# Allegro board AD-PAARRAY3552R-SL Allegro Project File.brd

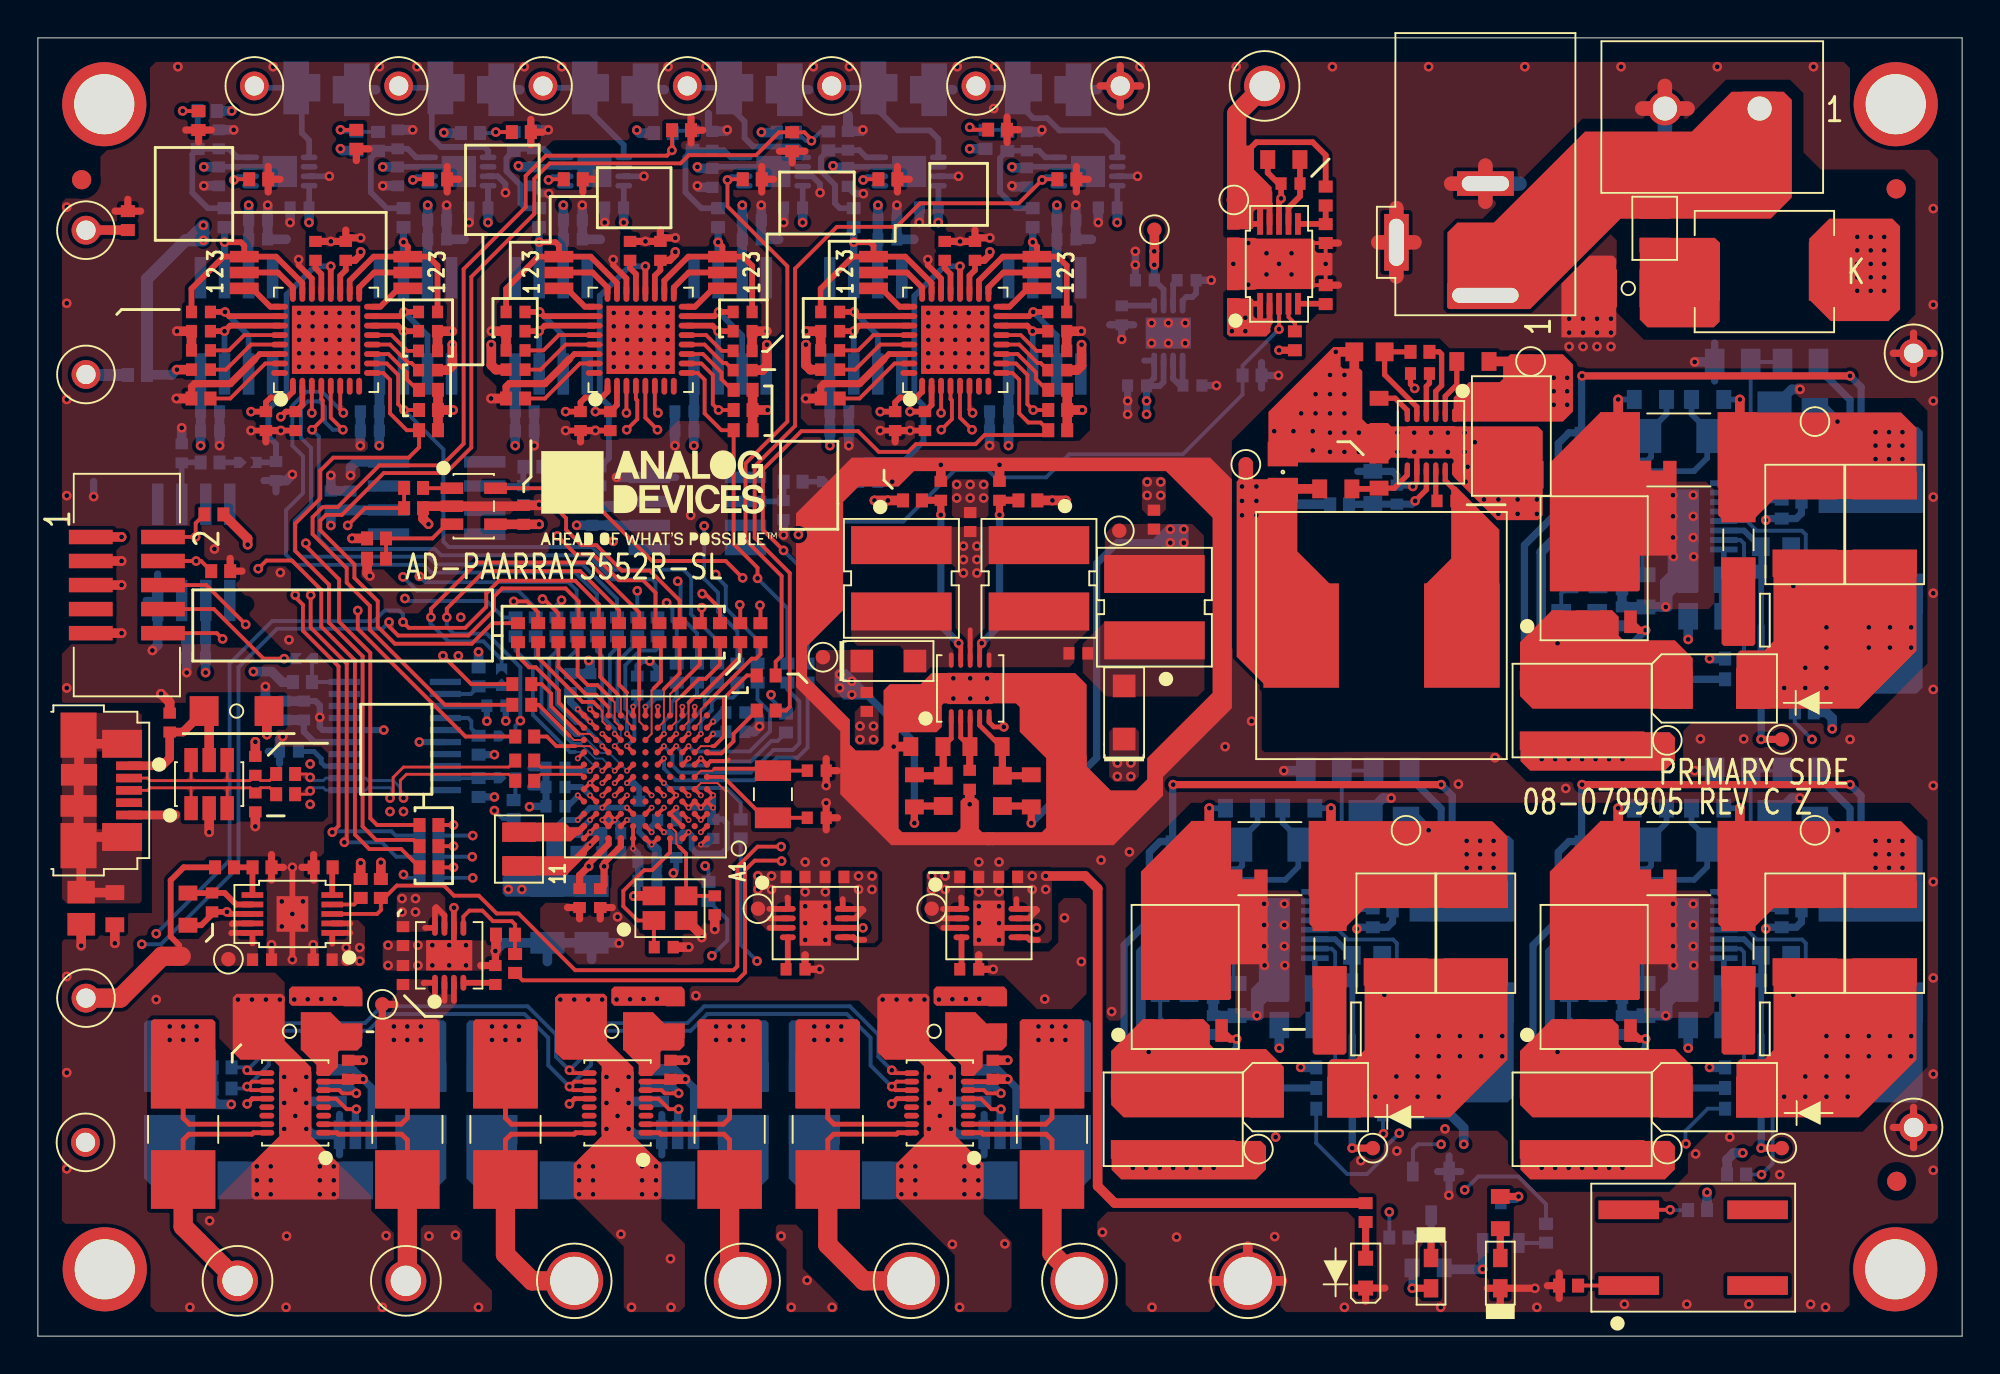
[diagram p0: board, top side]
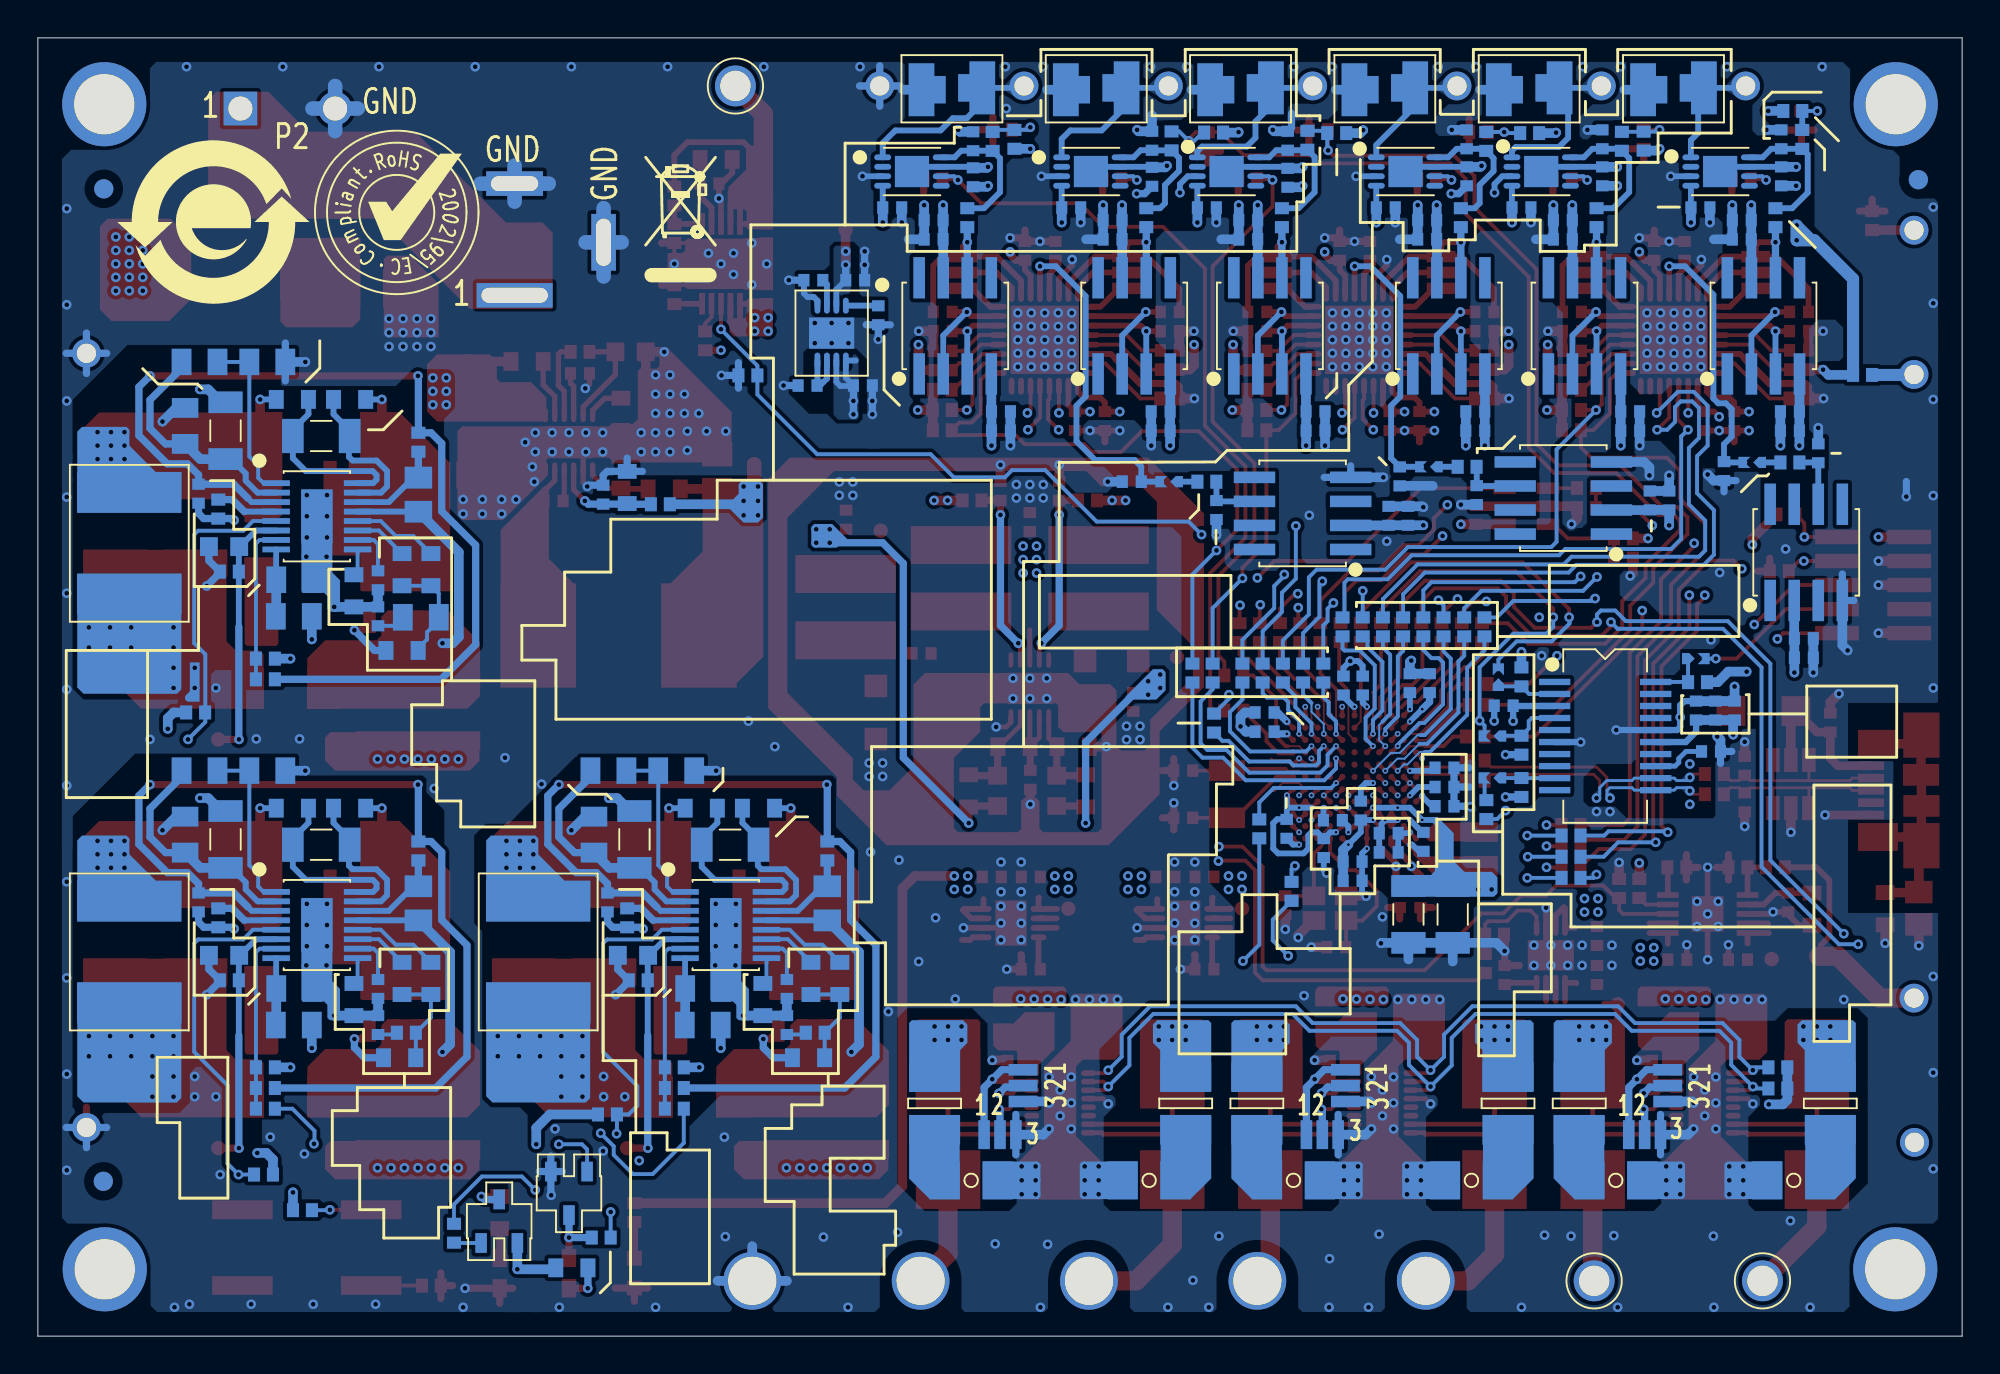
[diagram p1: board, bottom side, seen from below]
Outline 101.6 x 68.58 mm; copper layers: TOP, L2_GND, L3_SIG, L4_PWR, L5_GND, BOTTOM. Coordinates in mm from the lower left corner of the outline.
Outline path: 0,68.58 0,0 101.6,0 101.6,68.58 0,68.58

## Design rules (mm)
constraint set DEFAULT: min track width 0.203
net group DM_32666: nets DM_32666 UNNAMED_20_ADMAX3207E_I10_I
net group DP_32666: nets DP_32666 UNNAMED_20_ADMAX3207E_I10_I_1
net group USB_R: nets UNNAMED_19_ADMAX32666_I33_DM UNNAMED_19_ADMAX32666_I33_DP

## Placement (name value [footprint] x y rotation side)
A1  AD8065ARZ  [SO8]  43.71 53.37 180 bottom
A2  AD8065ARZ  [SO8]  53.16 53.37 180 bottom
A3  AD8065ARZ  [SO8]  27.1 53.37 180 bottom
A4  AD8065ARZ  [SO8]  36.55 53.37 180 bottom
A5  AD8065ARZ  [SO8]  10.49 53.37 180 bottom
A6  AD8065ARZ  [SO8]  19.94 53.37 180 bottom
C1  150NF  [C1206H71]  83.97 55.35 0 top
C2  10NF  [C1206H64]  89.79 20.47 90 top
C3  0.1uF  [C1206]  91.69 26.24 90 bottom
C4  22UF  [C2220H264]  96.77 20.29 90 bottom
C5  1UF  [C1812H100]  97.51 21.29 90 top
C6  1UF  [C1812H100]  93.29 21.29 90 top
C7  390PF  [C0603]  91.77 20.12 0 bottom
C8  0.1uF  [C1206]  86.64 25.96 0 bottom
C9  0.1UF  [C0805]  81.51 22.86 270 bottom
C10  1UF  [C0402]  83.64 16.43 90 bottom
C11  1NF  [C0402]  83.64 18.34 270 bottom
C12  1UF  [C0402]  93.12 22.91 270 bottom
C13  10NF  [C1206H64]  89.79 42.06 90 top
C14  22UF  [C2220H264]  96.77 41.88 90 bottom
C15  1UF  [C1812H100]  97.51 42.88 90 top
C16  1UF  [C1812H100]  93.29 42.88 90 top
C17  0.1uF  [C1206]  91.69 47.83 90 bottom
C18  390PF  [C0603]  91.77 41.71 0 bottom
C19  0.1uF  [C1206]  86.64 47.55 0 bottom
C20  0.1UF  [C0805]  81.51 44.45 270 bottom
C21  1UF  [C0402]  83.64 38.02 90 bottom
C22  1NF  [C0402]  83.64 39.93 270 bottom
C23  1UF  [C0402]  93.12 44.5 270 bottom
C24  4.7uF  [C0402]  63.12 55.04 90 top
C25  4.7uF  [C0402]  15.04 19.89 180 top
C26  4.7uF  [C0402]  19.28 21.13 270 top
C27  1UF  [C1812H100]  77.8 47.55 270 top
C28  0.056uF  [C0402]  72.97 50.85 180 top
C29  2.2UF  [C0603]  70.31 51.99 180 top
C30  1NF  [C0402]  24.16 19.08 90 top
C31  4.7uF  [C0402]  19.28 19.08 90 top
C32  4.7uF  [C0402]  66.14 60.88 180 top
C33  4.7uF  [C0402]  9.19 22.91 270 top
C34  100NF  [C0402]  74.37 44.12 180 top
C35  4.7uF  [C0402]  63.12 58.24 270 top
C36  4.7uF  [C0402]  11.84 19.89 0 top
C37  100NF  [C0402]  71.75 44.45 270 bottom
C38  6.8uF  [C0805H60]  65.74 45.64 90 top
C39  4.7uF  [C0402]  51.23 24.26 180 top
C40  4.7uF  [C0402]  42.06 24.26 180 top
C41  10UF  [C0402]  58.04 50.22 180 bottom
C42  1UF  [C0402]  60.66 55.78 0 bottom
C43  0.33uF  [C0402]  47.68 44.65 270 top
C44  4.7uF  [C0402]  49.23 43 90 top
C45  10UF  [C0402]  57.23 53.92 270 bottom
C46  1NF  [C0402]  49.17 19.38 0 top
C47  1NF  [C0402]  40 19.38 0 top
C48  0.33uF  [C0402]  50.77 44.65 270 top
C49  4.7uF  [C0402]  49.17 24.26 0 top
C50  4.7uF  [C0402]  40 24.26 0 top
C51  1UF  [C0402]  60.96 50.22 0 bottom
C52  10UF  [C0402]  58.45 55.78 180 bottom
C53  1UF  [C0402]  54.94 36.07 180 top
C54  10uF  [C0603_0805_1206_1210]  45.72 65.94 0 bottom
C55  0.1UF  [C0402]  49.2 29.39 270 top
C56  56PF  [C0603]  47.8 28.8 270 top
C57  56PF  [C0603]  50.93 28.8 90 top
C58  4.7uF  [C0402]  58.93 43.13 90 top
C59  4.7uF  [C0402]  43.76 33.5 270 top
C60  10uF  [C0603_0805_1206_1210]  53.34 65.94 0 bottom
C61  0.47uF  [C0402]  41.83 51.05 0 top
C62  0.47uF  [C0402]  53.82 51.03 180 top
C63  0.47uF  [C0402]  41.83 52.07 0 top
C64  0.47uF  [C0402]  53.82 52.04 180 top
C65  0.47uF  [C0402]  47.88 57.33 270 top
C66  1UF  [C0402]  49.48 57.33 90 top
C67  0.1UF  [C0402]  45.26 48.34 270 top
C68  0.1UF  [C0402]  46.84 48.34 270 top
C69  1UF  [C0402]  29.26 43.33 90 bottom
C70  1UF  [C0402]  30.28 43.33 90 bottom
C71  10PF  [C0402]  41.83 54.1 0 top
C72  0.1UF  [C0402]  41.83 53.09 0 top
C73  10PF  [C0402]  53.82 54.1 180 top
C74  0.1UF  [C0402]  53.82 53.09 180 top
C75  4.7uF  [C0402]  39.37 43.64 270 bottom
C76  0.1UF  [C0402]  42.32 48.84 0 bottom
C77  0.1UF  [C0402]  44.86 57.94 0 bottom
C78  0.1UF  [C0402]  50.75 48.84 180 bottom
C79  0.1UF  [C0402]  54.31 57.94 0 bottom
C80  0.1UF  [C0402]  43.84 45.14 0 bottom
C81  4.7uF  [C0402]  42.32 47.83 0 bottom
C82  4.7uF  [C0402]  44.86 58.95 0 bottom
C83  4.7uF  [C0402]  50.75 47.83 180 bottom
C84  4.7uF  [C0402]  54.31 58.95 0 bottom
C85  10PF  [C0402]  42.77 63.14 270 bottom
C86  10PF  [C0402]  52.22 63.12 270 bottom
C87  0.1UF  [C0402]  42.77 61.24 270 bottom
C88  0.1UF  [C0402]  52.22 61.21 270 bottom
C89  0.1UF  [C0402]  47.04 59.61 180 bottom
C90  0.1UF  [C0402]  56.49 59.61 180 bottom
C91  0.47uF  [C0402]  25.22 51.05 0 top
C92  0.47uF  [C0402]  37.21 51.03 180 top
C93  0.47uF  [C0402]  25.22 52.07 0 top
C94  0.47uF  [C0402]  37.21 52.04 180 top
C95  0.47uF  [C0402]  31.27 57.33 270 top
C96  1UF  [C0402]  32.87 57.33 90 top
C97  0.1UF  [C0402]  28.65 48.34 270 top
C98  0.1UF  [C0402]  30.23 48.34 270 top
C99  1UF  [C0402]  16.48 44.15 90 bottom
C100  1UF  [C0402]  15.47 44.15 90 bottom
C101  10PF  [C0402]  25.22 54.1 0 top
C102  0.1UF  [C0402]  25.22 53.09 0 top
C103  10PF  [C0402]  37.21 54.1 180 top
C104  0.1UF  [C0402]  37.21 53.09 180 top
C105  4.7uF  [C0402]  25.63 44.42 270 bottom
C106  0.1UF  [C0402]  25.7 48.84 0 bottom
C107  0.1UF  [C0402]  28.24 57.94 0 bottom
C108  0.1UF  [C0402]  34.14 48.84 180 bottom
C109  0.1UF  [C0402]  37.69 57.94 0 bottom
C110  0.1UF  [C0402]  29.69 45.42 270 bottom
C111  4.7uF  [C0402]  25.7 47.83 0 bottom
C112  4.7uF  [C0402]  28.24 58.95 0 bottom
C113  4.7uF  [C0402]  34.14 47.83 180 bottom
C114  4.7uF  [C0402]  37.69 58.95 0 bottom
C115  10PF  [C0402]  26.16 63.22 270 bottom
C116  10PF  [C0402]  35.61 63.14 270 bottom
C117  0.1UF  [C0402]  26.16 61.26 270 bottom
C118  0.1UF  [C0402]  35.61 61.19 270 bottom
C119  0.1UF  [C0402]  30.43 59.61 180 bottom
C120  0.1UF  [C0402]  39.88 59.61 180 bottom
C121  16pF  [C0402]  33.05 20.55 0 top
C122  1UF  [C0402]  41.12 27.38 0 top
C123  1UF  [C0402]  41.12 29.87 0 top
C124  16pF  [C0402]  35.74 22.76 270 top
C125  1UF  [C0402]  36.83 32.94 0 bottom
C126  100NF  [C0402]  32.66 34.37 90 bottom
C127  100NF  [C0402]  27.33 29.01 180 bottom
C128  47uF  [C1206]  26.9 22.28 270 bottom
C129  47uF  [C1206]  29.24 22.28 270 bottom
C130  1UF  [C0402]  36.83 31.93 0 bottom
C131  1UF  [C0402]  32.18 24.05 0 bottom
C132  1UF  [C0402]  31.65 34.37 90 bottom
C133  100NF  [C0402]  27.33 27.99 180 bottom
C134  1UF  [C0402]  32.18 25.07 0 bottom
C135  4.7NF  [C0402]  28.45 26.11 90 bottom
C136  1UF  [C0402]  27.33 30.02 180 bottom
C137  1UF  [C0402]  30.28 25.55 180 bottom
C138  1UF  [C0402]  35.66 26.8 270 bottom
C139  1UF  [C0402]  29.16 34.49 90 bottom
C140  1UF  [C0402]  28.12 34.49 90 bottom
C141  1UF  [C0402]  33.22 27.25 180 bottom
C142  1UF  [C0402]  33.71 25.78 90 bottom
C143  10NF  [C0402]  6.96 32.41 90 top
C144  47pF  [C0402]  11.48 28.19 270 top
C145  47pF  [C0402]  11.48 30.12 90 top
C146  1UF  [C0402]  12.01 33.05 90 bottom
C147  100NF  [C0402]  14.05 33.05 90 bottom
C148  4.7uF  [C0402]  13.03 33.05 90 bottom
C149  100NF  [C0402]  13.26 30.89 180 bottom
C150  100NF  [C0402]  24.21 33.3 0 bottom
C151  0.1uF  [C1206H71]  18.29 8.23 180 bottom
C152  0.1UF  [C0402]  16.38 14.07 90 top
C153  0.1uF  [C1206H71]  13.28 16.1 180 top
C154  0.1uF  [C1206H71]  8.89 8.23 0 bottom
C155  0.1UF  [C0402]  25.65 43.38 90 top
C156  10NF  [C1206H64]  68.2 20.47 90 top
C157  22UF  [C2220H264]  75.18 20.29 90 bottom
C158  1UF  [C1812H100]  75.92 21.29 90 top
C159  1UF  [C1812H100]  71.7 21.29 90 top
C160  0.1uF  [C1206]  70.1 26.24 90 bottom
C161  390PF  [C0603]  70.18 20.12 0 bottom
C162  0.1uF  [C1206]  65.05 25.96 0 bottom
C163  0.1UF  [C0805]  59.92 22.86 270 bottom
C164  1UF  [C0402]  62.05 16.43 90 bottom
C165  1NF  [C0402]  62.05 18.34 270 bottom
C166  1UF  [C0402]  71.53 22.91 270 bottom
C167  0.47uF  [C0402]  8.61 51.05 0 top
C168  0.47uF  [C0402]  20.6 51.03 180 top
C169  0.47uF  [C0402]  8.61 52.07 0 top
C170  0.47uF  [C0402]  20.6 52.04 180 top
C171  0.47uF  [C0402]  14.66 57.33 270 top
C172  1UF  [C0402]  16.26 57.33 90 top
C173  0.1UF  [C0402]  12.04 48.34 270 top
C174  0.1UF  [C0402]  13.61 48.34 270 top
C175  1UF  [C0402]  8.36 35.84 180 bottom
C176  1UF  [C0402]  8.36 36.86 180 bottom
C177  10PF  [C0402]  8.61 54.1 0 top
C178  0.1UF  [C0402]  8.61 53.09 0 top
C179  10PF  [C0402]  20.6 54.1 180 top
C180  0.1UF  [C0402]  20.6 53.09 180 top
C181  4.7uF  [C0402]  7.59 46.63 90 bottom
C182  0.1UF  [C0402]  9.09 48.84 0 bottom
C183  0.1UF  [C0402]  11.63 57.94 0 bottom
C184  0.1UF  [C0402]  17.53 48.84 180 bottom
C185  0.1UF  [C0402]  21.08 57.94 0 bottom
C186  0.1UF  [C0402]  12.57 45.69 270 bottom
C187  4.7uF  [C0402]  9.09 47.83 0 bottom
C188  4.7uF  [C0402]  11.63 58.95 0 bottom
C189  4.7uF  [C0402]  17.53 47.83 180 bottom
C190  4.7uF  [C0402]  21.08 58.95 0 bottom
C191  10PF  [C0402]  9.55 63.22 270 bottom
C192  10PF  [C0402]  19 63.22 270 bottom
C193  0.1UF  [C0402]  9.55 61.26 270 bottom
C194  0.1UF  [C0402]  19 61.26 270 bottom
C195  0.1UF  [C0402]  13.82 59.61 180 bottom
C196  0.1UF  [C0402]  23.27 59.61 180 bottom
C197  10uF  [C0603_0805_1206_1210]  15.24 65.94 0 bottom
C198  10uF  [C0603_0805_1206_1210]  22.86 65.94 0 bottom
C199  0.1uF  [C1206H71]  52.32 8.23 180 bottom
C200  0.1UF  [C0402]  50.42 14.07 90 top
C201  0.1uF  [C1206H71]  47.32 16.1 180 top
C202  0.1uF  [C1206H71]  42.93 8.23 0 bottom
C203  0.1uF  [C1206H71]  35.31 8.23 180 bottom
C204  0.1UF  [C0402]  33.4 14.07 90 top
C205  0.1uF  [C1206H71]  30.3 16.1 180 top
C206  0.1uF  [C1206H71]  25.91 8.23 0 bottom
C207  10uF  [C0603_0805_1206_1210]  30.48 65.94 0 bottom
C208  10uF  [C0603_0805_1206_1210]  38.1 65.94 0 bottom
C209  22UF  [C0402]  30.28 26.57 0 bottom
C210  22UF  [C0402]  28.6 23.14 90 top
C211  22UF  [C0402]  29.69 23.14 90 top
C212  22UF  [C0402]  31.75 27.76 270 bottom
D1  STPS5L60S  [SMC_A]  91.16 56.24 0 top
D2  ES1D-E3/61T  [DO214AC]  88.52 12.62 0 top
D3  ES1D-E3/61T  [DO214AC]  88.52 34.21 0 top
D4  PMEG2010AEH,115  [SOD123F]  44.91 35.66 0 top
D5  PMEG2010AEH,115  [SOD123F]  57.35 32.94 90 top
D8  ES1D-E3/61T  [DO214AC]  66.93 12.62 0 top
DS1  150060YS75000  [LED0603]  77.22 3.33 90 top
DS2  150060YS75000  [LED0603]  73.56 3.33 270 top
DS3  150060VS55040  [LED0603-2]  70.1 3.33 90 top
E1  220OHM  [L0805]  2.29 22.61 270 top
EN_DA  BLU  [CNKEY5001TP]  2.51 10.24 270 top
EN_SW  WHT  [CNKEY5001TP]  2.54 58.42 0 top
GND1  BLK  [CNKEY5001TP]  57.15 66.04 270 top
GND2  2501-2-00-80-00-00-07-0  [CNMILLMAX2501]  63.88 2.92 270 top
GND3  BLK  [CNKEY5001TP]  99.03 51.92 0 top
GND4  BLK  [CNKEY5001TP]  99.03 11.02 0 top
JP1  3PIN_SOLDER_JUMPER  [JPRSLD03]  52.76 56.18 90 top
JP2  3PIN_SOLDER_JUMPER  [JPRSLD03]  44.12 56.18 90 top
JP3  3PIN_SOLDER_JUMPER  [JPRSLD03]  36.14 56.18 90 top
JP4  3PIN_SOLDER_JUMPER  [JPRSLD03]  27.51 56.18 90 top
JP5  3PIN_SOLDER_JUMPER  [JPRSLD03]  15.54 13.23 270 bottom
JP6  3PIN_SOLDER_JUMPER  [JPRSLD03]  16.76 10.64 180 bottom
JP7  3PIN_SOLDER_JUMPER  [JPRSLD03]  19.53 56.18 90 top
JP8  3PIN_SOLDER_JUMPER  [JPRSLD03]  10.9 56.18 90 top
JP9  3PIN_SOLDER_JUMPER  [JPRSLD03]  49.58 13.23 270 bottom
JP10  3PIN_SOLDER_JUMPER  [JPRSLD03]  50.8 10.64 180 bottom
JP11  3PIN_SOLDER_JUMPER  [JPRSLD03]  32.56 13.23 270 bottom
JP12  3PIN_SOLDER_JUMPER  [JPRSLD03]  33.78 10.64 180 bottom
L1  1UH  [L0806H39]  85.37 58.52 270 top
L2  12UH  [IND-MSS1278]  70.94 37.01 180 top
L3  10UH  [LSMSQ189H161]  45.59 40.03 270 top
L4  10UH  [LSMSQ189H161]  52.86 40.03 270 top
L5  10UH  [LSMSQ189H161]  58.95 38.51 90 top
L6  2.2UH  [L0805_A]  25.4 25.73 90 top
L7  2000OHMS  [L1206]  10.49 33.02 0 top
NOREF  -  [unnamed]  3.53 3.53 0 top
NOREF#2  -  [#2]  51.74 61.49 0 top
NOREF#3  -  [#2]  68.38 106.23 0 top
NOREF#4  -  [unnamed]  98.15 8.18 0 top
NOREF#5  -  [#2]  44.12 61.49 0 top
NOREF#6  -  [unnamed]  2.31 61.09 0 top
NOREF#7  -  [#2]  28.23 63.31 0 top
NOREF#8  -  [#2]  36.5 62.23 0 top
NOREF#9  -  [#2]  0 0 90 top
NOREF#10  -  [#2]  51.09 63.31 0 top
NOREF#11  -  [#2]  -41.91 -129.54 0 top
NOREF#12  -  [#2]  153.14 96.44 0 top
NOREF#13  -  [#2]  32.49 44.25 0 top
NOREF#14  -  [#2]  44.12 62.23 0 top
NOREF#15  -  [#2]  -41.91 -129.54 0 top
NOREF#16  -  [#2]  28.88 61.49 0 top
NOREF#17  -  [#2]  12.99 63.31 0 top
NOREF#18  -  [#2]  21.26 62.23 0 top
NOREF#19  -  [#2]  43.47 63.31 0 top
NOREF#20  -  [unnamed]  3.51 65.07 0 top
NOREF#21  -  [unnamed]  98.09 65.07 0 top
NOREF#22  -  [#2]  21.26 64.93 0 top
NOREF#23  -  [#2]  13.64 61.49 0 top
NOREF#24  -  [#2]  0 0 0 top
NOREF#25  -  [#2]  51.74 64.93 0 top
NOREF#26  -  [#2]  36.5 64.93 0 top
NOREF#27  -  [#2]  13.64 62.23 0 top
NOREF#28  -  [#2]  51.74 62.23 0 top
NOREF#29  -  [#2]  53.97 85.85 0 top
NOREF#30  -  [#2]  13.64 64.93 0 top
NOREF#31  -  [#2]  20.61 63.31 0 top
NOREF#32  -  [#2]  0 68.58 0 top
NOREF#33  -  [#2]  44.12 64.93 0 top
NOREF#34  -  [#2]  0.7 28.87 0 top
NOREF#35  -  [#2]  -41.91 -129.54 0 top
NOREF#36  -  [unnamed]  98.07 3.53 0 top
NOREF#37  -  [#2]  36.5 61.49 0 top
NOREF#38  -  [#2]  21.26 61.49 0 top
NOREF#39  -  [#2]  0 68.58 270 top
NOREF#40  -  [#2]  117.47 210.41 0 top
NOREF#41  -  [#2]  28.88 62.23 0 top
NOREF#42  -  [unnamed]  98.12 60.6 0 top
NOREF#43  -  [#2]  35.85 63.31 0 top
NOREF#44  -  [#2]  28.88 64.93 0 top
NOREF#45  -  [unnamed]  98.15 8.18 180 bottom
NOREF#46  -  [#2]  82.65 59.36 180 bottom
NOREF#47  -  [#2]  101.6 0 180 bottom
NOREF#48  -  [unnamed]  2.31 61.09 180 bottom
NOREF#49  -  [#2]  92.33 58.85 180 bottom
NOREF#50  -  [#2]  101.6 68.58 270 bottom
NOREF#51  -  [unnamed]  98.12 60.6 180 bottom
NOREF#52  -  [#2]  67.87 55.73 180 bottom
P1  54-00130  [CNTENSILITY54-00130]  76.43 54.98 90 top
P2  OSTTC020162  [CNOSTTC0201X2]  90.91 64.85 180 top
P3  NCSOLDER_BRIDGE  [NCSB]  41.86 45.14 0 bottom
P4  NCSOLDER_BRIDGE  [NCSB]  28.14 45.92 0 bottom
P5  47346-0001  [CNMOLEX47346-0001]  2.5 28.83 270 top
P6  3220-10-0300-00  [CNSMMHDR2X5L443W201H228]  4.7 39.67 270 top
P7  NCSOLDER_BRIDGE  [NCSB]  24.79 29.49 0 bottom
P8  NCSOLDER_BRIDGE  [NCSB]  24.49 34.8 90 bottom
P9  NCSOLDER_BRIDGE  [NCSB]  24.79 31.7 0 bottom
P10  NCSOLDER_BRIDGE  [NCSB]  14.07 35.79 180 bottom
P11  NCSOLDER_BRIDGE  [NCSB]  11.07 46.15 0 bottom
Q1  BSC252N10NSFGATMA1  [SON8]  82.17 18.97 0 top
Q2  PMV65XP,215  [SOT23_B]  77.24 6.07 180 bottom
Q3  BSC252N10NSFGATMA1  [SON8]  82.17 40.56 0 top
Q4  PMV15UNEA  [SOT23_B]  73.56 7.54 0 bottom
Q5  BSC252N10NSFGATMA1  [SON8]  60.58 18.97 0 top
R1  100  [R1210]  91.19 16.23 180 top
R2  0  [R0805]  93.83 26.49 90 bottom
R3  1MEG  [R0805]  88.09 16.43 0 bottom
R4  22.6K  [R0805]  88.06 18.36 180 bottom
R5  0  [R0402]  92.07 22.1 270 bottom
R6  100K  [R0402]  91.49 18.8 0 bottom
R7  0  [R0603]  88.16 27.89 0 bottom
R8  10K  [R0402]  89.59 12.01 0 bottom
R9  0.015  [R2512H35]  86.64 25.22 180 top
R10  100  [R0603]  85.14 27.89 0 bottom
R11  0  [R0603]  80.85 18.9 90 bottom
R12  105K  [R0603]  84.91 17.78 270 bottom
R13  0  [R0603]  82.37 18.9 90 bottom
R14  0  [R0402]  82.14 16.03 180 bottom
R15  10  [R0603]  82.5 14.71 0 bottom
R16  0  [R0402]  81.51 25.63 90 bottom
R17  0  [R1225H28]  81.53 11.46 90 top
R18  10K  [R0402]  89.69 8.53 180 bottom
R19  0  [R0402]  79.63 5.44 270 bottom
R20  261  [R0603]  77.22 6.53 90 top
R21  100  [R1210]  91.19 37.82 180 top
R22  0  [R0805]  93.83 48.08 90 bottom
R23  221K  [R0805]  89.48 51.46 180 bottom
R24  1MEG  [R0805]  88.09 38.02 0 bottom
R25  21K  [R0805]  88.06 39.95 180 bottom
R26  1MEG  [R0805]  93.07 51.46 0 bottom
R27  0  [R0402]  92.07 43.69 270 bottom
R28  100K  [R0402]  91.49 40.39 0 bottom
R29  0  [R0603]  88.16 49.48 0 bottom
R30  10K  [R0402]  89.59 34.7 0 bottom
R31  0.015  [R2512H35]  86.64 46.81 180 top
R32  100  [R0603]  85.14 49.48 0 bottom
R33  0  [R0603]  80.85 40.49 90 bottom
R34  105K  [R0603]  84.91 39.37 270 bottom
R35  0  [R0603]  82.37 40.49 90 bottom
R36  0  [R0805]  81.38 37.97 180 bottom
R37  10  [R0603]  82.37 36.22 180 bottom
R38  0  [R0402]  81.51 47.22 90 bottom
R39  0  [R1225H28]  81.53 33.05 90 top
R40  10K  [R0402]  93.27 32.94 0 bottom
R41  976  [R0402]  39.83 63.09 270 top
R42  976  [R0402]  50.67 63.73 0 top
R43  200K  [R0402]  66.37 52.58 270 top
R44  200K  [R0402]  17.04 23.65 90 top
R45  499  [R0402]  68 55.02 270 top
R46  499  [R0402]  15.06 24.77 0 top
R47  0  [R0603]  75.77 51.49 180 top
R48  10K  [R0402]  72.97 51.99 0 top
R49  51.1K  [R0603]  70.82 48.69 90 top
R50  49.9K  [R0603]  65.79 62.15 0 top
R51  49.9K  [R0603]  7.92 22.56 90 top
R52  1MEG  [R0603]  70.48 44.83 270 bottom
R53  453K  [R0402]  68 60.22 90 top
R54  453K  [R0402]  9.86 24.77 180 top
R55  49.9K  [R0402]  68 58.24 90 top
R56  49.9K  [R0402]  11.84 24.77 180 top
R57  4.75  [R0402]  68.73 43.94 0 bottom
R58  0  [R0402]  5.26 50.77 180 bottom
R59  130K  [R0603]  68.53 44.75 180 top
R60  24.9K  [R0603]  70.82 45.64 270 top
R61  1K  [R0402]  70.1 6.53 90 top
R62  4.7K  [R0402]  46.18 44.15 180 top
R63  4.7K  [R0402]  52.27 44.15 0 top
R64  15K  [R0603]  50.06 31.14 180 top
R65  182K  [R0603]  52.45 28.8 90 top
R66  54.9K  [R0603]  46.28 28.8 270 top
R67  4.99K  [R0603]  46.94 31.14 0 top
R68  976  [R0402]  25.53 63.6 0 top
R69  976  [R0402]  33.99 63.7 0 top
R70  66.5K  [R0402]  41.83 49.53 0 top
R71  10K  [R0402]  53.85 47.85 180 top
R72  66.5K  [R0402]  53.85 48.92 180 top
R73  34K  [R0402]  53.85 49.99 0 top
R74  0  [R0402]  39.88 45.14 0 bottom
R75  0  [R0402]  43.08 59.08 90 bottom
R76  0  [R0402]  52.53 59.08 90 bottom
R77  1.78K  [R0402]  39.52 63.58 0 bottom
R78  10K  [R0402]  41.74 63.14 270 bottom
R79  1.78K  [R0402]  50.04 63.22 90 bottom
R80  10K  [R0402]  51.19 63.11 270 bottom
R81  66.5K  [R0402]  25.22 49.53 0 top
R82  10K  [R0402]  37.24 47.85 180 top
R83  66.5K  [R0402]  37.24 48.92 180 top
R84  34K  [R0402]  37.24 49.99 0 top
R85  0  [R0402]  26.14 45.92 0 bottom
R86  0  [R0402]  26.47 59.08 90 bottom
R87  0  [R0402]  35.92 59.08 90 bottom
R88  1.78K  [R0402]  22.83 63.55 0 bottom
R89  10K  [R0402]  25.13 63.11 270 bottom
R90  1.78K  [R0402]  33.02 63.55 0 bottom
R91  10K  [R0402]  34.57 63.17 270 bottom
R92  10K  [R0402]  87.63 6.65 180 bottom
R93  0  [R0402]  80.82 2.67 180 top
R94  1MEG  [R0603]  4.06 22.58 270 top
R95  27  [R0402]  13.08 28.63 0 top
R96  27  [R0402]  13.08 29.69 0 top
R97  10K  [R0402]  23.27 28.98 90 bottom
R98  10K  [R0402]  23.27 31.22 90 bottom
R99  10K  [R0402]  13.97 34.54 0 bottom
R100  10K  [R0402]  23.27 34.82 270 bottom
R101  10  [R1210]  20.22 12.29 270 bottom
R102  49.9  [R0603]  16.64 16.97 270 top
R103  0.025  [R2512H43]  19.51 10.92 270 top
R104  10  [R1210]  54.25 12.29 270 bottom
R105  1.5K  [R0402]  9.73 14.2 180 bottom
R106  49.9  [R0603]  50.67 16.97 270 top
R107  0.025  [R2512H43]  7.67 10.92 90 top
R108  1.5K  [R0402]  9.73 13.08 180 bottom
R109  10  [R1210]  6.96 12.29 270 bottom
R110  2K  [R0402]  19.84 43.74 0 top
R111  2.49K  [R0402]  19.84 44.81 180 top
R112  100  [R1210]  69.6 16.23 180 top
R113  0  [R0805]  72.24 26.49 90 bottom
R114  1MEG  [R0805]  66.5 16.43 0 bottom
R115  22.6K  [R0805]  66.47 18.36 180 bottom
R116  0  [R0402]  70.48 22.1 270 bottom
R117  100K  [R0402]  69.9 18.8 0 bottom
R118  0  [R0603]  66.57 27.89 0 bottom
R119  10K  [R0402]  68 12.01 0 bottom
R120  0.015  [R2512H35]  65.05 25.22 180 top
R121  100  [R0603]  63.55 27.89 0 bottom
R122  0  [R0603]  59.26 18.9 90 bottom
R123  105K  [R0603]  63.32 17.78 270 bottom
R124  0  [R0603]  60.78 18.9 90 bottom
R125  0  [R0402]  60.55 16.03 0 bottom
R126  10  [R0603]  60.91 14.71 0 bottom
R127  0  [R0402]  59.92 25.63 90 bottom
R128  0  [R1225H28]  59.94 11.46 90 top
R129  10K  [R0402]  71.53 11.71 0 bottom
R130  976  [R0402]  8.48 64.21 270 top
R131  976  [R0402]  16.81 63.22 270 top
R132  66.5K  [R0402]  8.61 49.53 0 top
R133  10K  [R0402]  20.62 47.85 180 top
R134  66.5K  [R0402]  20.62 48.92 180 top
R135  34K  [R0402]  20.62 49.99 0 top
R136  0  [R0402]  9.09 46.15 0 bottom
R137  0  [R0402]  9.86 59.08 90 bottom
R138  0  [R0402]  19.3 59.08 90 bottom
R139  1.78K  [R0402]  8.94 64.72 180 bottom
R140  10K  [R0402]  8.44 63.22 270 bottom
R141  1.78K  [R0402]  16.81 63.12 90 bottom
R142  10K  [R0402]  17.97 63.12 270 bottom
R143  0.025  [R2512H43]  53.54 10.92 270 top
R144  0  [R0402]  17.88 42.14 180 top
R145  0.025  [R2512H43]  41.71 10.92 90 top
R146  0  [R0402]  17.88 41.07 0 top
R147  10  [R1210]  41 12.29 270 bottom
R148  10  [R1210]  37.24 12.29 270 bottom
R149  49.9  [R0603]  33.66 16.97 270 top
R150  0.025  [R2512H43]  36.53 10.92 270 top
R152  0.025  [R2512H43]  24.69 10.92 90 top
R154  10  [R1210]  23.98 12.29 270 bottom
R155  10K  [R0402]  64.11 50.75 0 bottom
R156  1MEG  [R0805]  93.07 29.87 180 bottom
R157  10K  [R0402]  18.11 23.65 90 top
R158  0  [R0402]  25.2 19.69 90 top
R159  10K  [R0402]  24.69 21.21 180 top
R160  29.4K  [R0805]  67.89 29.87 180 bottom
R161  10K  [R0402]  44.88 61.11 0 top
R162  10K  [R0402]  54.33 61.11 0 top
R163  10K  [R0402]  28.27 61.11 0 top
R164  10K  [R0402]  37.72 61.11 0 top
R165  10K  [R0402]  11.66 61.11 0 top
R166  10K  [R0402]  21.11 61.11 0 top
R167  10K  [R0402]  4.75 58.93 90 top
R171  10K  [R0402]  9.3 43.41 180 top
R172  29.4K  [R0805]  89.48 29.87 180 bottom
R173  10K  [R0402]  9.65 40.41 0 top
R174  10K  [R0402]  89.59 13.11 0 bottom
R175  10K  [R0402]  89.59 14.2 0 bottom
R176  10K  [R0402]  89.59 35.79 0 bottom
R177  1MEG  [R0805]  71.48 29.87 180 bottom
R178  10K  [R0402]  68 13.11 0 bottom
R179  10K  [R0402]  68 14.2 0 bottom
R180  0  [R0402]  35.41 23.49 90 bottom
R181  0  [R0402]  31.75 37.16 270 top
R182  0  [R0402]  30.68 37.16 270 top
R185  0  [R0402]  40.64 35.03 270 bottom
R186  0  [R0402]  39.57 35.03 270 bottom
R187  0  [R0402]  37.11 26.8 90 bottom
R188  0  [R0402]  25.35 37.16 270 top
R189  0  [R0402]  28.45 37.47 270 bottom
R190  0  [R0402]  25.22 37.47 270 bottom
R191  0  [R0402]  25.55 33.35 0 top
R192  0  [R0402]  25.55 34.44 0 top
R193  0  [R0402]  25.7 31.67 0 top
R194  0  [R0402]  20.65 26.44 0 bottom
R195  0  [R0402]  20.65 27 0 top
R196  0  [R0402]  20.65 25.88 0 top
R197  0  [R0402]  26.29 37.47 270 bottom
R198  0  [R0402]  30.58 37.47 270 bottom
R199  0  [R0402]  29.51 37.47 270 bottom
R200  0  [R0402]  32.72 37.47 270 bottom
R201  0  [R0402]  31.65 37.47 270 bottom
R202  0  [R0402]  20.65 24.21 180 bottom
R203  0  [R0402]  27.38 37.47 90 bottom
R204  0  [R0402]  25.7 30.4 180 top
R205  0  [R0402]  25.7 29.34 180 top
R206  0  [R0402]  25.12 27.81 90 bottom
R207  0  [R0402]  32.82 37.16 90 top
R208  0  [R0402]  33.88 37.16 90 top
R209  0  [R0402]  26.42 37.16 90 top
R210  0  [R0402]  27.48 37.16 90 top
R211  0  [R0402]  29.62 37.16 90 top
R212  0  [R0402]  28.55 37.16 90 top
R215  0  [R0402]  38.15 37.16 90 top
R216  0  [R0402]  37.08 37.16 90 top
R217  0  [R0402]  38 35.03 90 bottom
R218  0  [R0402]  38.46 34.9 0 top
R219  0  [R0402]  20.65 24.77 180 top
R220  0  [R0402]  20.65 25.32 180 bottom
R223  0  [R0402]  34.95 37.16 90 top
R224  0  [R0402]  36.02 37.16 90 top
R225  0  [R0402]  33.73 35.03 90 bottom
R226  0  [R0402]  34.8 35.03 90 bottom
R227  0  [R0402]  35.86 35.03 90 bottom
R228  0  [R0402]  36.93 35.03 90 bottom
R229  0  [R0402]  39.5 32.38 90 bottom
R230  0  [R0402]  38.46 33.05 0 top
R236  1K  [R0402]  71.86 5.21 180 bottom
R237  261  [R0603]  73.41 3.61 0 bottom
S3  EVQ-Q2K03W  [SWPANASONIC_EVQ]  87.4 4.67 0 top
TP1  TESTPAD  [TPSMC30]  93.83 26.72 0 top
TP2  TESTPAD  [TPSMC30]  92.07 9.93 0 top
TP3  TESTPAD  [TPSMC30]  86.03 9.88 270 top
TP4  TESTPAD  [TPSMC30]  93.83 48.31 0 top
TP5  TESTPAD  [TPSMC30]  92.07 31.52 0 top
TP6  TESTPAD  [TPSMC30]  86.03 31.47 270 top
TP7  TESTPAD  [TPSMC30]  78.82 51.49 270 top
TP8  TESTPAD  [TPSMC30]  18.19 17.53 180 top
TP9  TESTPAD  [TPSMC30]  63.14 60.02 0 top
TP10  TESTPAD  [TPSMC30]  10.06 19.91 90 top
TP11  TESTPAD  [TPSMC30]  63.78 46.05 0 top
TP12  TESTPAD  [TPSMC30]  47.19 22.58 90 top
TP13  TESTPAD  [TPSMC30]  38.02 22.58 270 top
TP14  TESTPAD  [TPSMC30]  58.95 58.45 180 top
TP15  TESTPAD  [TPSMC30]  41.45 35.86 180 top
TP16  TESTPAD  [TPSMC30]  57.1 42.55 180 top
TP20  TESTPAD  [TPSMC30]  72.24 26.72 0 top
TP21  TESTPAD  [TPSMC30]  70.48 9.93 0 top
TP22  TESTPAD  [TPSMC30]  64.44 9.88 270 top
U1  LTC7000IMSE#TRPBF  [MSOP16_PAD2_845X1_651]  86.87 21.72 270 bottom
U2  LTC7000IMSE#TRPBF  [MSOP16_PAD2_845X1_651]  86.87 43.31 270 bottom
U3  ADM7172ACPZ-5.0  [DFN8_3X3_PAD2_44X1_6_A]  21.72 20.12 0 top
U4  LT3042IMSE#TRPBF  [MSOP10_PAD1_88X1_68]  65.53 56.64 0 top
U5  LT3042IMSE#TRPBF  [MSOP10_PAD1_88X1_68]  13.44 22.3 90 top
U6  MAX17643ATC+  [DFN12_3X3_PAD2_5X1_7]  73.56 47.22 180 top
U7  ADM7170ACPZ-3.3  [DFN8_3X3_PAD2_38X1_64]  50.22 21.82 270 top
U8  ADM7170ACPZ-1.8  [DFN8_3X3_PAD2_38X1_64]  41.05 21.82 270 top
U9  ADM7150ACPZ-5.0-R7  [DFN8_3X3_PAD2_38X1_64]  59.69 52.98 0 bottom
U10  LT3471EDD#PBF  [QFN10_3X3_PAD2_38X1_64]  49.23 34.21 0 top
U12  AD3552RBCPZ16  [QFN32_5X5_PAD3_6X3_6]  48.44 52.63 0 top
U13  ADR4525CRZ  [SO8]  34.82 43.46 90 bottom
U14  ADG1401BCPZ  [DFN8_2X3_PAD1_65X1_80]  46 61.52 270 bottom
U15  ADG1401BCPZ  [DFN8_2X3_PAD1_65X1_80]  55.45 61.52 270 bottom
U16  AD3552RBCPZ16  [QFN32_5X5_PAD3_6X3_6]  31.83 52.63 0 top
U17  ADR4525CRZ  [SO8]  21.06 44.27 90 bottom
U18  ADG1401BCPZ  [DFN8_2X3_PAD1_65X1_80]  29.39 61.52 270 bottom
U19  ADG1401BCPZ  [DFN8_2X3_PAD1_65X1_80]  38.84 61.52 270 bottom
U20  MAX32666GXMBT+  [BGA121H41]  32.08 29.54 90 top
U21  MAX3207EAUT+  [SOT23_6]  9.04 29.16 0 top
U22  FT231XS-R  [SSOP20-3]  18.85 31.7 270 bottom
U23  LTC2992HDE#PBF  [DFN16_4X3_PAD3_3X1_7]  13.59 12.32 90 top
U24  MAX6516UKP075+  [SOT23-5L-2]  23.01 43.84 270 top
U25  LTC7000IMSE#TRPBF  [MSOP16_PAD2_845X1_651]  65.28 21.72 270 bottom
U26  AD3552RBCPZ16  [QFN32_5X5_PAD3_6X3_6]  15.21 52.63 0 top
U27  ADR4525CRZ  [SO8]  8.23 41.4 180 bottom
U28  ADG1401BCPZ  [DFN8_2X3_PAD1_65X1_80]  12.78 61.52 270 bottom
U29  ADG1401BCPZ  [DFN8_2X3_PAD1_65X1_80]  22.23 61.52 270 bottom
U30  LTC2992HDE#PBF  [DFN16_4X3_PAD3_3X1_7]  47.62 12.32 90 top
U31  LTC2992HDE#PBF  [DFN16_4X3_PAD3_3X1_7]  30.61 12.32 90 top
UNK5V_DA  BLU  [CNKEY5001TP]  2.54 17.86 0 top
UNK5V_PDA  5124  [CNKEY5005-9TP]  64.77 66.04 270 top
UNK5V_SW  WHT  [CNKEY5001TP]  2.54 50.8 0 top
VD1  2501-2-00-80-00-00-07-0  [CNMILLMAX2501]  37.21 2.92 90 top
VD2  2501-2-00-80-00-00-07-0  [CNMILLMAX2501]  28.32 2.92 0 top
VDC1  5121  [CNKEY5005-9TP]  19.43 2.92 0 top
VDC2  2501-2-00-80-00-00-07-0  [CNMILLMAX2501]  54.99 2.92 0 top
VDP1  5121  [CNKEY5005-9TP]  10.54 2.92 0 top
VDP2  2501-2-00-80-00-00-07-0  [CNMILLMAX2501]  46.1 2.92 90 top
VG1  ORG  [CNKEY5001TP]  11.43 66.04 0 top
VG2  ORG  [CNKEY5001TP]  19.05 66.04 270 top
VGC1  YEL  [CNKEY5001TP]  26.67 66.04 0 top
VGC2  RED  [CNKEY5001TP]  41.91 66.04 0 top
VGP1  YEL  [CNKEY5001TP]  34.29 66.04 270 top
VGP2  RED  [CNKEY5001TP]  49.53 66.04 0 top
Y1  32MEGHZ  [YSML98W79H26]  33.38 22.61 0 top
Y2  32.7680KHZ  [YSML126W59H35]  38.81 28.63 90 top

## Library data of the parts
A1-A6 = AD8065: Tolerance: N/A; User Part Number: UPN; alternate symbols: (SO8); part number: AD8065_SM-AD8065ARZ,E017201,SO8; tolerance: N/A
C1 = CAP: Tolerance: 10; User Part Number: UPN; alternate symbols: (C1206H71); part number: CAP_SM-150NF,100V,10,E057967,C1206H71; tolerance: 10
C2 C13 C156 = CAP: User Part Number: UPN; Tolerance: 20; alternate symbols: (C1206H64); part number: CAP_SM-10NF,500V,20,E042690,C1206H64; tolerance: 20
C3 C8 C17 C19 C160 C162 = CAP: User Part Number: UPN; Tolerance: 10; alternate symbols: (C1206); part number: CAP_SM-0.1UF,200V,10,E022724,C1206; tolerance: 10
C4 C14 C157 = CAP: User Part Number: UPN; Tolerance: 20; alternate symbols: (C2220H264); part number: CAP_SM-22UF,100V,20,E057255,C2220H264; tolerance: 20
C5 C6 C15 C16 C27 C158 C159 = CAP: Tolerance: 10; User Part Number: UPN; alternate symbols: (C1812H100); part number: CAP_SM-1UF,250V,10,E047335,C1812H100; tolerance: 10
C7 C18 C161 = CAP: User Part Number: UPN; Tolerance: 5; alternate symbols: (C0603); part number: CAP_SM-390PF,100V,5,E044557,C0603; tolerance: 5
C9 C20 C163 = CAP: User Part Number: UPN; Tolerance: 10; alternate symbols: (C0805); part number: CAP_SM-0.1UF,50V,10,E062481,C0805; tolerance: 10
C10 C12 C21 C23 C53 C146 C164 C166 = CAP: User Part Number: UPN; Tolerance: 10; alternate symbols: (C0402); part number: CAP_SM-1UF,25V,10,E054542,C0402; tolerance: 10
C11 C22 C30 C46 C47 C165 = CAP: User Part Number: UPN; Tolerance: 10; alternate symbols: (C0402); part number: CAP_SM-1NF,25V,10,E042764,C0402; tolerance: 10
C24-C26 C31-C33 C35 C36 C39 C40 C44 C49 C50 C58 C59 C75 C81-C84 C111-C114 C148 C187-C190 = CAP: User Part Number: UPN; Tolerance: 20; alternate symbols: (C0402); part number: CAP_SM-4.7UF,16V,20,E034700,C0402; tolerance: 20
C28 = CAP: User Part Number: UPN; Tolerance: 0.1; alternate symbols: (C0402); part number: CAP_SM-0.056UF,16V,0.1,E019786,C0402; tolerance: 0.1
C29 = CAP: User Part Number: UPN; Tolerance: 10; alternate symbols: (C0603); part number: CAP_SM-2.2UF,16V,10,E054576,C0603; tolerance: 10
C34 C37 C126 C127 C133 C147 C149 C150 = CAP: User Part Number: UPN; Tolerance: 10; alternate symbols: (C0402); part number: CAP_SM-100NF,25V,10,E060176,C0402; tolerance: 10
C38 = CAP: Tolerance: 20; User Part Number: UPN; alternate symbols: (C0805H60); part number: CAP_SM-6.8UF,16V,20,E034691,C0805H60; tolerance: 20
C41 C45 C52 = CAP: User Part Number: UPN; Tolerance: 20; alternate symbols: (C0402); part number: CAP_SM-10UF,10V,20,E061569,C0402; tolerance: 20
C42 C51 C69 C70 C99 C100 C122 C123 C125 C130-C132 C134 C136-C142 C175 C176 = CAP: User Part Number: UPN; Tolerance: 10; alternate symbols: (C0402); part number: CAP_SM-1UF,10V,10,E056342,C0402; tolerance: 10
C43 C48 = CAP: User Part Number: UPN; Tolerance: 10; alternate symbols: (C0402); part number: CAP_SM-0.33UF,10V,10,E033835,C0402; tolerance: 10
C54 C60 C197 C198 C207 C208 = CAP: User Part Number: UPN; Tolerance: N/A; alternate symbols: (C0603_0805_1206_1210); part number: CAP_SM-10UF,N/A,N/A,E029817,C0603_0805_1206_1210; tolerance: N/A
C55 C67 C68 C72 C74 C76-C80 C87-C90 C97 C98 C102 C104 C106-C110 C117-C120 C152 C155 C173 C174 C178 C180 C182-C186 C193-C196 C200 C204 = CAP: User Part Number: UPN; Tolerance: 20; alternate symbols: (C0402); part number: CAP_SM-0.1UF,16V,20,E062928,C0402; tolerance: 20
C56 C57 = CAP: User Part Number: UPN; Tolerance: 5; alternate symbols: (C0603); part number: CAP_SM-56PF,50V,5,E042665,C0603; tolerance: 5
C61-C65 C91-C95 C167-C171 = CAP: User Part Number: UPN; Tolerance: 10; alternate symbols: (C0402); part number: CAP_SM-0.47UF,10V,10,E035987,C0402; tolerance: 10
C66 C96 C172 = CAP: User Part Number: UPN; Tolerance: 10; alternate symbols: (C0402); part number: CAP_SM-1UF,4V,10,E060901,C0402; tolerance: 10
C71 C73 C85 C86 C101 C103 C115 C116 C177 C179 C191 C192 = CAP: User Part Number: UPN; Tolerance: 10; alternate symbols: (C0402); part number: CAP_SM-10PF,16V,10,E042801,C0402; tolerance: 10
C105 C181 = CAP: User Part Number: UPN; Tolerance: 20; alternate symbols: (C0402); part number: CAP_SM-4.7UF,6.3V,20,E041637,C0402; tolerance: 20
C121 C124 = CAP: User Part Number: UPN; Tolerance: 2; alternate symbols: (C0402); part number: CAP_SM-16PF,50V,2,E021463,C0402; tolerance: 2
C128 C129 = CAP: User Part Number: UPN; Tolerance: 20; alternate symbols: (C1206); part number: CAP_SM-47UF,6.3V,20,E006154,C1206; tolerance: 20
C135 = CAP: User Part Number: UPN; Tolerance: 10; alternate symbols: (C0402); part number: CAP_SM-4.7NF,16V,10,E042800,C0402; tolerance: 10
C143 = CAP: User Part Number: UPN; Tolerance: 5; alternate symbols: (C0402); part number: CAP_SM-10NF,16V,5,E042671,C0402; tolerance: 5
C144 C145 = CAP: User Part Number: UPN; Tolerance: 5; alternate symbols: (C0402); part number: CAP_SM-47PF,50V,5,E011821,C0402; tolerance: 5
C151 C153 C154 C199 C201-C203 C205 C206 = CAP: Tolerance: 10; User Part Number: UPN; alternate symbols: (C1206H71); part number: CAP_SM-0.1UF,100V,10,E033449,C1206H71; tolerance: 10
C209-C212 = CAP: User Part Number: UPN; Tolerance: 20; alternate symbols: (C0402); part number: CAP_SM-22UF,10V,20,E053186,C0402; tolerance: 20
D1 = DIOSCHOTTKY_V3: User Part Number: UPN; Tolerance: N/A; alternate symbols: (SMC_A); part number: DIOSCHOTTKY_V3_SM-STPS5L60S,60V,N/A,E061973,SMC_A; tolerance: N/A
D2 D3 D8 = DIO: User Part Number: UPN; Tolerance: N/A; alternate symbols: (DO214AC); part number: DIO_SM-ES1D-E3/61T,200V,N/A,E010463,DO214AC; tolerance: N/A
D4 D5 = DIOSCHOTTKY: Tolerance: N/A; User Part Number: UPN; alternate symbols: (SOD123F); part number: DIOSCHOTTKY_SM-PMEG2010AEH,115,20V,N/A,E016182,SOD123F; tolerance: N/A
DS1 DS2 = DIOLED: Tolerance: N/A; User Part Number: UPN; alternate symbols: (LED0603); part number: DIOLED_SM-150060YS75000,5V,N/A,E044494,LED0603; tolerance: N/A
DS3 = DIOLED: Tolerance: N/A; User Part Number: UPN; alternate symbols: (LED0603-2); part number: DIOLED_SM-150060VS55040,2.4V,N/A,E056632,LED0603-2; tolerance: N/A
E1 = FERRITE: User Part Number: UPN; Tolerance: 25; alternate symbols: (L0805); part number: FERRITE_SM-220OHM,25,E017491,L0805; tolerance: 25
EN_DA UNK5V_DA = CNTP1P: Tolerance: N/A; User Part Number: UPN; alternate symbols: (CNKEY5001TP); part number: CNTP1P_TH-BLU,E016322,CNKEY5001TP; tolerance: N/A
EN_SW UNK5V_SW = CNTP1P: Tolerance: N/A; User Part Number: UPN; alternate symbols: (CNKEY5001TP); part number: CNTP1P_TH-WHT,E006153,CNKEY5001TP; tolerance: N/A
GND1 GND3 GND4 = CNTP1P: Tolerance: N/A; User Part Number: UPN; alternate symbols: (CNKEY5001TP); part number: CNTP1P_TH-BLK,E005347,CNKEY5001TP; tolerance: N/A
GND2 VD1 VD2 VDC2 VDP2 = CNTP1P: User Part Number: UPN; Tolerance: N/A; alternate symbols: (CNMILLMAX2501); part number: CNTP1P_TH-2501-2-00-80-00-00-07-0,E031108,CNMILLMAX2501; tolerance: N/A
JP1-JP12 = NC3P_JMPR: Tolerance: N/A; User Part Number: UPN; alternate symbols: (JPRSLD03); part number: NC3P_JMPR_SM-3PIN_SOLDER_JUMPER,E005606,JPRSLD03; tolerance: N/A
L1 = IND: Tolerance: 20; User Part Number: UPN; alternate symbols: (L0806H39); part number: IND_SM-1UH,20,E060133,L0806H39; tolerance: 20
L2 = IND: Tolerance: 20; User Part Number: UPN; alternate symbols: (IND-MSS1278); part number: IND_SM-12UH,20,E048163,IND-MSS1278; tolerance: 20
L3-L5 = IND: Tolerance: 20; User Part Number: UPN; alternate symbols: (LSMSQ189H161); part number: IND_SM-10UH,20,E060765,LSMSQ189H161; tolerance: 20
L6 = IND: Tolerance: 20; User Part Number: UPN; alternate symbols: (L0805_A); part number: IND_SM-2.2UH,20,E025569,L0805_A; tolerance: 20
L7 = IND: Tolerance: 25; User Part Number: UPN; alternate symbols: (L1206); part number: IND_SM-2000OHMS,25,E002365,L1206; tolerance: 25
P1 = CN3P_V6: User Part Number: UPN; Tolerance: N/A; alternate symbols: (CNTENSILITY54-00130); part number: CN3P_V6_TH-54-00130,E035595,CNTENSILITY54-00130; tolerance: N/A
P2 = CN2P: Tolerance: N/A; User Part Number: UPN; alternate symbols: (CNOSTTC0201X2); part number: CN2P_TH-OSTTC020162,E034806,CNOSTTC0201X2; tolerance: N/A
P3 P4 P7-P11 = NC2P: User Part Number: UPN; Tolerance: N/A; alternate symbols: (NCSB); part number: NC2P_SM-NCSOLDER_BRIDGE,E043778,NCSB; tolerance: N/A
P5 = CN5P_6GND: User Part Number: UPN; Tolerance: N/A; alternate symbols: (CNMOLEX47346-0001); part number: CN5P_6GND_SM-47346-0001,E023846,CNMOLEX47346-0001; tolerance: N/A
P6 = CN10P: User Part Number: UPN; Tolerance: N/A; alternate symbols: (CNSMMHDR2X5L443W201H228); part number: CN10P_SM-3220-10-0300-00,E027502,CNSMMHDR2X5L443W201H228; tolerance: N/A
Q1 Q3 Q5 = TRANNMOSFET8P: Tolerance: N/A; User Part Number: UPN; alternate symbols: (SON8); part number: TRANNMOSFET8P_SM-BSC252N10NSFGATMA1,E042206,SON8; tolerance: N/A
Q2 = TRANPMOSFET_V12: User Part Number: UPN; Tolerance: N/A; alternate symbols: (SOT23_B); part number: TRANPMOSFET_V12_SM-PMV65XP,215,E027303,SOT23_B; tolerance: N/A
Q4 = TRANNMOSFET_V26: User Part Number: UPN; Tolerance: N/A; alternate symbols: (SOT23_B); part number: TRANNMOSFET_V26_SM-PMV15UNEA,E061099,SOT23_B; tolerance: N/A
R1 R21 R112 = RES: Tolerance: 5; User Part Number: UPN; alternate symbols: (R1210); part number: RES_SM-100,E063354,1/2W,5,R1210; tolerance: 5
R2 R22 R36 R113 = RES: User Part Number: UPN; Tolerance: 1; alternate symbols: (R0805); part number: RES_SM-0,E059953,1/8W,1,R0805; tolerance: 1
R3 R24 R26 R114 R156 R177 = RES: User Part Number: UPN; Tolerance: 1; alternate symbols: (R0805); part number: RES_SM-1MEG,E003518,1/8W,1,R0805; tolerance: 1
R4 R115 = RES: User Part Number: UPN; Tolerance: 0.1; alternate symbols: (R0805); part number: RES_SM-22.6K,E018659,1/8W,0.1,R0805; tolerance: 0.1
R5 R14 R16 R19 R27 R38 R58 R74-R76 R85-R87 R93 R116 R125 R127 R136-R138 R144 R146 R158 R180-R182 R185-R212 R215-R220 R223-R230 = RES: User Part Number: UPN; Tolerance: JUMPER; alternate symbols: (R0402); part number: RES_SM-0,E003438,1/10W,JUMPER,R0402; tolerance: JUMPER
R6 R28 R117 = RES: User Part Number: UPN; Tolerance: 5; alternate symbols: (R0402); part number: RES_SM-100K,E003464,1/10W,5,R0402; tolerance: 5
R7 R11 R13 R29 R33 R35 R47 R118 R122 R124 = RES: User Part Number: UPN; Tolerance: JUMPER; alternate symbols: (R0603); part number: RES_SM-0,E027148,1/4W,JUMPER,R0603; tolerance: JUMPER
R8 R18 R30 R40 R48 R71 R78 R80 R82 R89 R91 R92 R97-R100 R119 R129 R133 R140 R142 R155 R157 R159 R161-R167 R171 R173-R176 R178 R179 = RES: User Part Number: UPN; Tolerance: 1; alternate symbols: (R0402); part number: RES_SM-10K,E030849,1/16W,1,R0402; tolerance: 1
R9 R31 R120 = RES: User Part Number: UPN; Tolerance: 1; alternate symbols: (R2512H35); part number: RES_SM-0.015,E051318,1W,1,R2512H35; tolerance: 1
R10 R32 R121 = RES: User Part Number: UPN; Tolerance: 1; alternate symbols: (R0603); part number: RES_SM-100,E028138,1/4W,1,R0603; tolerance: 1
R12 R34 R123 = RES: User Part Number: UPN; Tolerance: 1; alternate symbols: (R0603); part number: RES_SM-105K,E019711,1/10W,1,R0603; tolerance: 1
R15 R37 R126 = RES: User Part Number: UPN; Tolerance: 1; alternate symbols: (R0603); part number: RES_SM-10,E049770,1/4W,1,R0603; tolerance: 1
R17 R39 R128 = RES: User Part Number: UPN; Tolerance: N/A; alternate symbols: (R1225H28); part number: RES_SM-0,E048848,2W,N/A,R1225H28; tolerance: N/A
R20 R237 = RES: User Part Number: UPN; Tolerance: 1; alternate symbols: (R0603); part number: RES_SM-261,E056811,1/10W,1,R0603; tolerance: 1
R23 = RES: User Part Number: UPN; Tolerance: 1; alternate symbols: (R0805); part number: RES_SM-221K,E042902,1/8W,1,R0805; tolerance: 1
R25 = RES: User Part Number: UPN; Tolerance: 1; alternate symbols: (R0805); part number: RES_SM-21K,E018107,1/8W,1,R0805; tolerance: 1
R41 R42 R68 R69 R130 R131 = RES: User Part Number: UPN; Tolerance: 1; alternate symbols: (R0402); part number: RES_SM-976,E005781,1/10W,1,R0402; tolerance: 1
R43 R44 = RES: User Part Number: UPN; Tolerance: 1; alternate symbols: (R0402); part number: RES_SM-200K,E004033,1/10W,1,R0402; tolerance: 1
R45 R46 = RES: User Part Number: UPN; Tolerance: 1; alternate symbols: (R0402); part number: RES_SM-499,E003758,1/10W,1,R0402; tolerance: 1
R49 = RES: User Part Number: UPN; Tolerance: 1; alternate symbols: (R0603); part number: RES_SM-51.1K,E026198,1/10W,1,R0603; tolerance: 1
R50 R51 = RES: User Part Number: UPN; Tolerance: 1; alternate symbols: (R0603); part number: RES_SM-49.9K,E015342,1/10W,1,R0603; tolerance: 1
R52 R94 = RES: User Part Number: UPN; Tolerance: 1; alternate symbols: (R0603); part number: RES_SM-1MEG,E061732,1/4W,1,R0603; tolerance: 1
R53 R54 = RES: User Part Number: UPN; Tolerance: 1; alternate symbols: (R0402); part number: RES_SM-453K,E027660,1/10W,1,R0402; tolerance: 1
R55 R56 = RES: User Part Number: UPN; Tolerance: 1; alternate symbols: (R0402); part number: RES_SM-49.9K,E004901,1/10W,1,R0402; tolerance: 1
R57 = RES: User Part Number: UPN; Tolerance: 1; alternate symbols: (R0402); part number: RES_SM-4.75,E031929,1/16W,1,R0402; tolerance: 1
R59 = RES: User Part Number: UPN; Tolerance: 5; alternate symbols: (R0603); part number: RES_SM-130K,E042750,1/10W,5,R0603; tolerance: 5
R60 = RES: User Part Number: UPN; Tolerance: 1; alternate symbols: (R0603); part number: RES_SM-24.9K,E030453,1/10W,1,R0603; tolerance: 1
R61 R236 = RES: User Part Number: UPN; Tolerance: 1; alternate symbols: (R0402); part number: RES_SM-1K,E049923,1/16W,1,R0402; tolerance: 1
R62 R63 = RES: User Part Number: UPN; Tolerance: 5; alternate symbols: (R0402); part number: RES_SM-4.7K,E042730,1/10W,5,R0402; tolerance: 5
R64 = RES: User Part Number: UPN; Tolerance: 0.1; alternate symbols: (R0603); part number: RES_SM-15K,E003957,1/10W,0.1,R0603; tolerance: 0.1
R65 = RES: User Part Number: UPN; Tolerance: 0.1; alternate symbols: (R0603); part number: RES_SM-182K,E041595,1/10W,0.1,R0603; tolerance: 0.1
R66 = RES: User Part Number: UPN; Tolerance: 1; alternate symbols: (R0603); part number: RES_SM-54.9K,E056715,1/10,1,R0603; tolerance: 1
R67 = RES: User Part Number: UPN; Tolerance: 1; alternate symbols: (R0603); part number: RES_SM-4.99K,E003726,1/10W,1,R0603; tolerance: 1
R70 R72 R81 R83 R132 R134 = RES: User Part Number: UPN; Tolerance: 1; alternate symbols: (R0402); part number: RES_SM-66.5K,E019641,1/16W,1,R0402; tolerance: 1
R73 R84 R135 = RES: User Part Number: UPN; Tolerance: 1; alternate symbols: (R0402); part number: RES_SM-34K,E043037,1/10W,1,R0402; tolerance: 1
R77 R79 R88 R90 R139 R141 = RES: User Part Number: UPN; Tolerance: 1; alternate symbols: (R0402); part number: RES_SM-1.78K,E032108,1/10W,1,R0402; tolerance: 1
R95 R96 = RES: User Part Number: UPN; Tolerance: 0.5; alternate symbols: (R0402); part number: RES_SM-27,E059283,1/16W,0.5,R0402; tolerance: 0.5; signal model: RES_SM-27_E059283_1/16W_0.5_R0402-R0402_27
R101 R104 R109 R147 R148 R154 = RES: Tolerance: 1; User Part Number: UPN; alternate symbols: (R1210); part number: RES_SM-10,E015972,1/2W,1,R1210; tolerance: 1
R102 R106 R149 = RES: User Part Number: UPN; Tolerance: 1; alternate symbols: (R0603); part number: RES_SM-49.9,E021630,1/5W,1,R0603; tolerance: 1
R103 R107 R143 R145 R150 R152 = RES: User Part Number: UPN; Tolerance: 1; alternate symbols: (R2512H43); part number: RES_SM-0.025,E028463,3W,1,R2512H43; tolerance: 1
R105 R108 = RES: User Part Number: UPN; Tolerance: 1; alternate symbols: (R0402); part number: RES_SM-1.5K,E003782,1/10W,1,R0402; tolerance: 1
R110 = RES: User Part Number: UPN; Tolerance: 1; alternate symbols: (R0402); part number: RES_SM-2K,E003752,1/10W,1,R0402; tolerance: 1
R111 = RES: User Part Number: UPN; Tolerance: 1; alternate symbols: (R0402); part number: RES_SM-2.49K,E007345,1/10W,1,R0402; tolerance: 1
R160 R172 = RES: User Part Number: UPN; Tolerance: 1; alternate symbols: (R0805); part number: RES_SM-29.4K,E018575,1/8W,1,R0805; tolerance: 1
S3 = SWSPST4PIN_B: Tolerance: N/A; User Part Number: UPN; alternate symbols: (SWPANASONIC_EVQ); part number: SWSPST4PIN_B_SM-EVQ-Q2K03W,E039231,SWPANASONIC_EVQ; tolerance: N/A
TP1-TP16 TP20-TP22 = NCTESTPAD: Tolerance: N/A; User Part Number: UPN; alternate symbols: (TPSMC30); part number: NCTESTPAD_SM-TESTPAD,E012884,TPSMC30; tolerance: N/A
U1 U2 U25 = ADLTC7000: Tolerance: N/A; User Part Number: UPN; alternate symbols: (MSOP16_PAD2_845X1_651); part number: ADLTC7000_SM-LTC7000IMSE#TRPBF,E038312 A,MSOP16_PAD2_845X1_651; tolerance: N/A
U3 = ADM7172: Tolerance: N/A; User Part Number: UPN; alternate symbols: (DFN8_3X3_PAD2_44X1_6_A); part number: ADM7172_SM-ADM7172ACPZ-5.0,E022886,DFN8_3X3_PAD2_44X1_6_A; tolerance: N/A
U4 U5 = LINLT3042: User Part Number: UPN; Tolerance: N/A; alternate symbols: (MSOP10_PAD1_88X1_68); part number: LINLT3042_SM-LT3042IMSE#TRPBF,E041293,MSOP10_PAD1_88X1_68; tolerance: N/A
U6 = ADMAX17643: User Part Number: UPN; Tolerance: N/A; alternate symbols: (DFN12_3X3_PAD2_5X1_7); part number: ADMAX17643_SM-MAX17643ATC+,E060682,DFN12_3X3_PAD2_5X1_7; tolerance: N/A
U7 = ADM7170: Tolerance: N/A; User Part Number: UPN; alternate symbols: (DFN8_3X3_PAD2_38X1_64); part number: ADM7170_SM-ADM7170ACPZ-3.3,E022590,DFN8_3X3_PAD2_38X1_64; tolerance: N/A
U8 = ADM7170: Tolerance: N/A; User Part Number: UPN; alternate symbols: (DFN8_3X3_PAD2_38X1_64); part number: ADM7170_SM-ADM7170ACPZ-1.8,E022558,DFN8_3X3_PAD2_38X1_64; tolerance: N/A
U9 = ADM7150: Tolerance: N/A; User Part Number: UPN; alternate symbols: (DFN8_3X3_PAD2_38X1_64); part number: ADM7150_SM-ADM7150ACPZ-5.0-R7,E018417,DFN8_3X3_PAD2_38X1_64; tolerance: N/A
U10 = LINLT3471: User Part Number: UPN; Tolerance: N/A; alternate symbols: (QFN10_3X3_PAD2_38X1_64); part number: LINLT3471_SM-LT3471EDD#PBF,E030330,QFN10_3X3_PAD2_38X1_64; tolerance: N/A
U12 U16 U26 = AD3552R: Tolerance: N/A; User Part Number: UPN; alternate symbols: (QFN32_5X5_PAD3_6X3_6); part number: AD3552R_SM-AD3552RBCPZ16,E035588,QFN32_5X5_PAD3_6X3_6; tolerance: N/A
U13 U17 U27 = ADR45XX: Tolerance: N/A; User Part Number: UPN; alternate symbols: (SO8); part number: ADR45XX_SM-ADR4525CRZ,E058062,SO8; tolerance: N/A
U14 U15 U18 U19 U28 U29 = ADG1401: Tolerance: N/A; User Part Number: UPN; alternate symbols: (DFN8_2X3_PAD1_65X1_80); part number: ADG1401_SM-ADG1401BCPZ,E013447,DFN8_2X3_PAD1_65X1_80; tolerance: N/A
U20 = ADMAX32666: User Part Number: UPN; Tolerance: N/A; alternate symbols: (BGA121H41); part number: ADMAX32666_SM-MAX32666GXMBT+,E057155,BGA121H41; tolerance: N/A
U21 = ADMAX3207E: User Part Number: UPN; Tolerance: N/A; alternate symbols: (SOT23_6); part number: ADMAX3207E_SM-MAX3207EAUT+,E059110,SOT23_6; tolerance: N/A
U22 = ICFT231XS: Tolerance: N/A; User Part Number: UPN; alternate symbols: (SSOP20-3); part number: ICFT231XS_SM-FT231XS-R,E021292,SSOP20-3; tolerance: N/A
U23 U30 U31 = ADLTC2992: User Part Number: UPN; Tolerance: N/A; alternate symbols: (DFN16_4X3_PAD3_3X1_7); part number: ADLTC2992_SM-LTC2992HDE#PBF,E045536,DFN16_4X3_PAD3_3X1_7; tolerance: N/A
U24 = ADMAX6516: User Part Number: UPN; Tolerance: N/A; alternate symbols: (SOT23-5L-2); part number: ADMAX6516_SM-MAX6516UKP075+,E062656,SOT23-5L-2; tolerance: N/A
UNK5V_PDA = CNTP1P: Tolerance: N/A; User Part Number: UPN; alternate symbols: (CNKEY5005-9TP); part number: CNTP1P_TH-5124,E056877,CNKEY5005-9TP; tolerance: N/A
VDC1 VDP1 = CNTP1P: Tolerance: N/A; User Part Number: UPN; alternate symbols: (CNKEY5005-9TP); part number: CNTP1P_TH-5121,E056050,CNKEY5005-9TP; tolerance: N/A
VG1 VG2 = CNTP1P: Tolerance: N/A; User Part Number: UPN; alternate symbols: (CNKEY5001TP); part number: CNTP1P_TH-ORG,E029026,CNKEY5001TP; tolerance: N/A
VGC1 VGP1 = CNTP1P: Tolerance: N/A; User Part Number: UPN; alternate symbols: (CNKEY5001TP); part number: CNTP1P_TH-YEL,E016321,CNKEY5001TP; tolerance: N/A
VGC2 VGP2 = CNTP1P: Tolerance: N/A; User Part Number: UPN; alternate symbols: (CNKEY5001TP); part number: CNTP1P_TH-RED,E016323,CNKEY5001TP; tolerance: N/A
Y1 = XTAL4PIN_V3: Tolerance: 10ppm; User Part Number: UPN; alternate symbols: (YSML98W79H26); part number: XTAL4PIN_V3_SM-32MEGHZ,E058951,YSML98W79H26; tolerance: 10ppm
Y2 = XTAL: User Part Number: UPN; Tolerance: 20PPM; alternate symbols: (YSML126W59H35); part number: XTAL_SM-32.7680KHZ,E050683,YSML126W59H35; tolerance: 20PPM

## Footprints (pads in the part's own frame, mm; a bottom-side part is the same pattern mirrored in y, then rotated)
BGA121H41
  round 0.33 smd: A1(-3.25,-3.25) A2(-3.25,-2.6) A3(-3.25,-1.95) A4(-3.25,-1.3) A5(-3.25,-0.65) A6(-3.25,0) A7(-3.25,0.65) A8(-3.25,1.3) A9(-3.25,1.95) A10(-3.25,2.6) A11(-3.25,3.25) B1(-2.6,-3.25) B2(-2.6,-2.6) B3(-2.6,-1.95) B4(-2.6,-1.3) B5(-2.6,-0.65) B6(-2.6,0) B7(-2.6,0.65) B8(-2.6,1.3) B9(-2.6,1.95) B10(-2.6,2.6) B11(-2.6,3.25) C1(-1.95,-3.25) C2(-1.95,-2.6) C3(-1.95,-1.95) C4(-1.95,-1.3) C5(-1.95,-0.65) C6(-1.95,0) C7(-1.95,0.65) C8(-1.95,1.3) C9(-1.95,1.95) C10(-1.95,2.6) C11(-1.95,3.25) D1(-1.3,-3.25) D2(-1.3,-2.6) D3(-1.3,-1.95) D4(-1.3,-1.3) D5(-1.3,-0.65) D6(-1.3,0) D7(-1.3,0.65) D8(-1.3,1.3) D9(-1.3,1.95) D10(-1.3,2.6) D11(-1.3,3.25) E1(-0.65,-3.25) E2(-0.65,-2.6) E3(-0.65,-1.95) E4(-0.65,-1.3) E5(-0.65,-0.65) E6(-0.65,0) E7(-0.65,0.65) E8(-0.65,1.3) E9(-0.65,1.95) E10(-0.65,2.6) E11(-0.65,3.25) F1(0,-3.25) F2(0,-2.6) F3(0,-1.95) F4(0,-1.3) F5(0,-0.65) F6(0,0) F7(0,0.65) F8(0,1.3) F9(0,1.95) F10(0,2.6) F11(0,3.25) G1(0.65,-3.25) G2(0.65,-2.6) G3(0.65,-1.95) G4(0.65,-1.3) G5(0.65,-0.65) G6(0.65,0) G7(0.65,0.65) G8(0.65,1.3) G9(0.65,1.95) G10(0.65,2.6) G11(0.65,3.25) H1(1.3,-3.25) H2(1.3,-2.6) H3(1.3,-1.95) H4(1.3,-1.3) H5(1.3,-0.65) H6(1.3,0) H7(1.3,0.65) H8(1.3,1.3) H9(1.3,1.95) H10(1.3,2.6) H11(1.3,3.25) J1(1.95,-3.25) J2(1.95,-2.6) J3(1.95,-1.95) J4(1.95,-1.3) J5(1.95,-0.65) J6(1.95,0) J7(1.95,0.65) J8(1.95,1.3) J9(1.95,1.95) J10(1.95,2.6) J11(1.95,3.25) K1(2.6,-3.25) K2(2.6,-2.6) K3(2.6,-1.95) K4(2.6,-1.3) K5(2.6,-0.65) K6(2.6,0) K7(2.6,0.65) K8(2.6,1.3) K9(2.6,1.95) K10(2.6,2.6) K11(2.6,3.25) L1(3.25,-3.25) L2(3.25,-2.6) L3(3.25,-1.95) L4(3.25,-1.3) L5(3.25,-0.65) L6(3.25,0) L7(3.25,0.65) L8(3.25,1.3) L9(3.25,1.95) L10(3.25,2.6) L11(3.25,3.25)
C0402
  rect 0.584x0.66 smd: 1(-0.5,0) 2(0.5,0)
C0603
  rect 0.94x0.991 smd: 1(-0.8,0) 2(0.8,0)
C0603_0805_1206_1210
  custom 0.489x0.489 smd: 1(-1.306,0) 2(1.306,0.1)
C0805
  rect 1.143x1.448 smd: 1(-0.9,0) 2(0.9,0)
C0805H60
  rect 1.295x1.6 smd: 1(-0.953,0) 2(0.953,0)
C1206
  rect 1.143x1.803 smd: 1(-1.5,0) 2(1.5,0)
C1206H64
  rect 1.143x1.803 smd: 1(-1.5,0) 2(1.5,0)
C1206H71
  rect 1.6x2.007 smd: 1(-1.397,0) 2(1.397,0)
C1812H100
  rect 1.448x3.404 smd: 1(-2.05,0) 2(2.05,0)
C2220H264
  rect 2.159x5.512 smd: 1(-2.685,0) 2(2.685,0)
CNKEY5001TP
  round 1.524 hole 1.016: 1(0,0)
CNKEY5005-9TP
  round 2.159 hole 1.6: 1(0,0)
CNMILLMAX2501
  round 3.048 hole 2.54: 1(0,0)
CNMOLEX47346-0001
  rect 0.457x1.372 smd: 1(-1.3,2.314) 2(-0.65,2.314) 3(0,2.314) 4(0.65,2.314) 5(1.3,2.314)
  rect 1.473x2.108 smd: G1(-2.462,1.946) G2(2.462,1.946)
  rect 2.388x1.905 smd: G3(2.919,-0.35) G6(-2.919,-0.35)
  rect 1.143x1.905 smd: G4(0.821,-0.35) G5(-0.821,-0.33)
CNOSTTC0201X2
  rect 1.778x1.778 hole 1.27: 1(0,0)
  round 1.778 hole 1.27: 2(5,0)
CNSMMHDR2X5L443W201H228
  rect 0.762x2.311 smd: 1(-2.54,-1.906) 2(-2.54,1.906) 3(-1.27,-1.906) 4(-1.27,1.906) 5(0,-1.906) 6(0,1.906) 7(1.27,-1.906) 8(1.27,1.906) 9(2.54,-1.906) 10(2.54,1.906)
CNTENSILITY54-00130
  rect 1.295x4.013 hole 0.787x3.505: 1(0,0)
  rect 1.295x2.997 hole 0.787x2.489: 2(5.9,0)
  rect 2.997x1.295 hole 2.489x0.787: 3(2.8,4.7)
